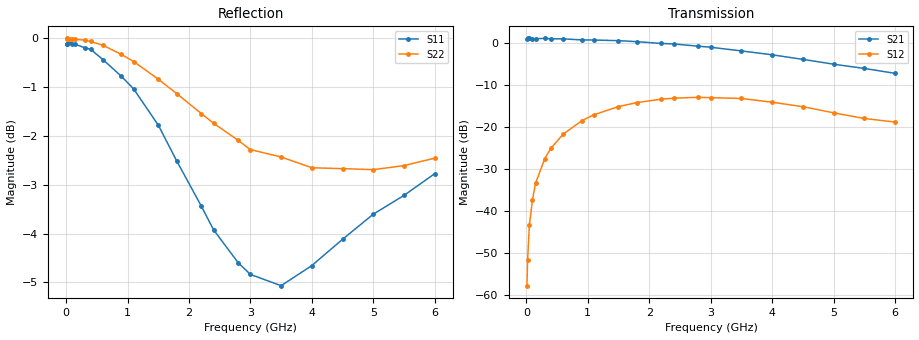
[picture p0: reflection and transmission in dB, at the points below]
! SIEMENS Small Signal Semiconductors
! BFP181
! Si NPN RF Bipolar Junction Transistor in SOT143
! VCE = 4 V  IC = 0.3 mA
! Common Emitter S-Parameters:  March  1996
# GHz  S  MA  R  50
!  f  S11  S21  S12  S22
! GHz  MAG  ANG  MAG  ANG  MAG  ANG  MAG  ANG
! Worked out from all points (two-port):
!   36 points, 10 MHz to 6 GHz, reference 50 ohm
!   highest |S21| = 1.05 dB at 300 MHz (marker M1); lowest = -7.3 dB at 6 GHz (marker M2)
!   |S21| within 3 dB of the highest: start of sweep to 3.51 GHz
!   lowest |S11| = -5.1 dB at 3.5 GHz (marker M3), VSWR 3.52, Z = 14.3 + j4.42 ohm
!   |S11| at or under -10 dB: nowhere
!   |S22| runs from -2.7 to 0.0 dB; largest |S21 - S12| = 1.1
!   S11 on the Smith chart (normalised r, x): 10 MHz: open; 900 MHz: 0.33, -2.51; 1.8 GHz: 0.28, -0.97; 2.8 GHz: 0.28, -0.26; 4 GHz: 0.29, +0.30; 6 GHz: 0.31, +0.97
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0.01  0.9874 -0.7  1.116 179.8  0.0013 79.4  0.9998 -0.2
0.02  0.9861 -1.0  1.126 179.9  0.0026 92.1  0.9989 -0.5
0.05  0.9913 -2.3  1.125 177.4  0.0069 90.3  0.9987 -1.2
0.1  0.9863 -4.6  1.114 175.0  0.0137 84.6  0.9989 -2.4
0.15  0.9858 -7.2  1.118 172.6  0.0214 84.2  0.9974 -3.5
0.3  0.9781 -14.4  1.129 165.7  0.042 79.2  0.9957 -7.1
0.4  0.9741 -19.0  1.117 159.8  0.0558 76.1  0.9925 -9.5
0.6  0.9509 -28.4  1.114 150.3  0.0822 68.7  0.9836 -14.2
0.9  0.9142 -42.9  1.082 135.8  0.1182 58.1  0.9626 -21.0
1.1  0.8873 -52.9  1.079 126.5  0.1397 51.4  0.9466 -25.3
1.5  0.8148 -73.4  1.06 108.9  0.1745 38.7  0.908 -33.6
1.8  0.7489 -89.3  1.032 95.1  0.195 30.1  0.8777 -39.2
2.2  0.6732 -112.0  0.982 78.1  0.2139 18.5  0.8374 -46.5
2.4  0.6366 -123.8  0.969 70.5  0.2197 13.0  0.8185 -50.0
2.8  0.5891 -148.8  0.911 54.8  0.2252 3.2  0.7861 -56.4
3  0.5729 -161.3  0.886 47.1  0.223 -1.9  0.769 -59.8
3.5  0.5579 169.0  0.801 29.6  0.218 -12.7  0.7558 -68.0
4  0.585 144.2  0.72 14.8  0.1968 -21.7  0.7368 -77.5
4.5  0.6224 124.8  0.636 1.5  0.1741 -28.9  0.7353 -87.9
5  0.6604 110.1  0.557 -9.3  0.1473 -32.3  0.7335 -98.7
5.5  0.6903 98.3  0.496 -18.4  0.1262 -29.8  0.7406 -109.6
6  0.7266 89.1  0.434 -25.7  0.1144 -24.9  0.7537 -120.9
